VERSION 5.7 ;
  NOWIREEXTENSIONATPIN ON ;
  DIVIDERCHAR "/" ;
  BUSBITCHARS "[]" ;
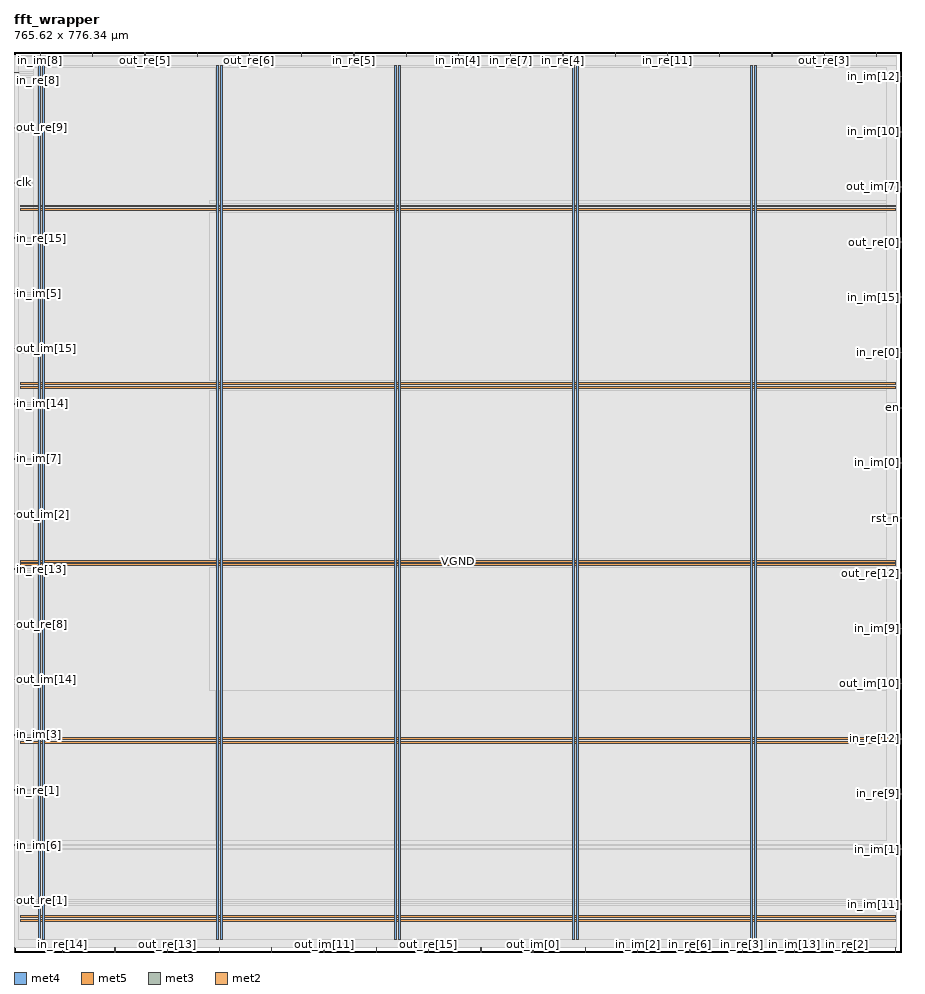
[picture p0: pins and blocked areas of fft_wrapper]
MACRO fft_wrapper
  CLASS BLOCK ;
  FOREIGN fft_wrapper ;
  ORIGIN 0.000 0.000 ;
  SIZE 765.620 BY 776.340 ;
  PIN VGND
    DIRECTION INOUT ;
    USE GROUND ;
    PORT
      LAYER met4 ;
        RECT 24.340 10.640 25.940 764.560 ;
    END
    PORT
      LAYER met4 ;
        RECT 177.940 10.640 179.540 764.560 ;
    END
    PORT
      LAYER met4 ;
        RECT 331.540 10.640 333.140 764.560 ;
    END
    PORT
      LAYER met4 ;
        RECT 485.140 10.640 486.740 764.560 ;
    END
    PORT
      LAYER met4 ;
        RECT 638.740 10.640 640.340 764.560 ;
    END
    PORT
      LAYER met5 ;
        RECT 5.280 30.030 760.160 31.630 ;
    END
    PORT
      LAYER met5 ;
        RECT 5.280 183.210 760.160 184.810 ;
    END
    PORT
      LAYER met5 ;
        RECT 5.280 336.390 760.160 337.990 ;
    END
    PORT
      LAYER met5 ;
        RECT 5.280 489.570 760.160 491.170 ;
    END
    PORT
      LAYER met5 ;
        RECT 5.280 642.750 760.160 644.350 ;
    END
  END VGND
  PIN VPWR
    DIRECTION INOUT ;
    USE POWER ;
    PORT
      LAYER met4 ;
        RECT 21.040 10.640 22.640 764.560 ;
    END
    PORT
      LAYER met4 ;
        RECT 174.640 10.640 176.240 764.560 ;
    END
    PORT
      LAYER met4 ;
        RECT 328.240 10.640 329.840 764.560 ;
    END
    PORT
      LAYER met4 ;
        RECT 481.840 10.640 483.440 764.560 ;
    END
    PORT
      LAYER met4 ;
        RECT 635.440 10.640 637.040 764.560 ;
    END
    PORT
      LAYER met5 ;
        RECT 5.280 26.730 760.160 28.330 ;
    END
    PORT
      LAYER met5 ;
        RECT 5.280 179.910 760.160 181.510 ;
    END
    PORT
      LAYER met5 ;
        RECT 5.280 333.090 760.160 334.690 ;
    END
    PORT
      LAYER met5 ;
        RECT 5.280 486.270 760.160 487.870 ;
    END
    PORT
      LAYER met5 ;
        RECT 5.280 639.450 760.160 641.050 ;
    END
  END VPWR
  PIN clk
    DIRECTION INPUT ;
    USE SIGNAL ;
    ANTENNAGATEAREA 1.286700 ;
    ANTENNADIFFAREA 0.434700 ;
    PORT
      LAYER met3 ;
        RECT 0.000 663.040 4.000 663.640 ;
    END
  END clk
  PIN en
    DIRECTION INPUT ;
    USE SIGNAL ;
    ANTENNAGATEAREA 0.247500 ;
    PORT
      LAYER met3 ;
        RECT 761.620 469.240 765.620 469.840 ;
    END
  END en
  PIN in_im[0]
    DIRECTION INPUT ;
    USE SIGNAL ;
    ANTENNAGATEAREA 0.247500 ;
    PORT
      LAYER met3 ;
        RECT 761.620 421.640 765.620 422.240 ;
    END
  END in_im[0]
  PIN in_im[10]
    DIRECTION INPUT ;
    USE SIGNAL ;
    ANTENNAGATEAREA 0.495000 ;
    PORT
      LAYER met3 ;
        RECT 761.620 707.240 765.620 707.840 ;
    END
  END in_im[10]
  PIN in_im[11]
    DIRECTION INPUT ;
    USE SIGNAL ;
    ANTENNAGATEAREA 0.426000 ;
    PORT
      LAYER met3 ;
        RECT 761.620 40.840 765.620 41.440 ;
    END
  END in_im[11]
  PIN in_im[12]
    DIRECTION INPUT ;
    USE SIGNAL ;
    ANTENNAGATEAREA 0.742500 ;
    PORT
      LAYER met3 ;
        RECT 761.620 754.840 765.620 755.440 ;
    END
  END in_im[12]
  PIN in_im[13]
    DIRECTION INPUT ;
    USE SIGNAL ;
    ANTENNAGATEAREA 0.426000 ;
    PORT
      LAYER met2 ;
        RECT 673.070 0.000 673.350 4.000 ;
    END
  END in_im[13]
  PIN in_im[14]
    DIRECTION INPUT ;
    USE SIGNAL ;
    ANTENNAGATEAREA 0.247500 ;
    PORT
      LAYER met3 ;
        RECT 0.000 472.640 4.000 473.240 ;
    END
  END in_im[14]
  PIN in_im[15]
    DIRECTION INPUT ;
    USE SIGNAL ;
    ANTENNAGATEAREA 0.426000 ;
    PORT
      LAYER met3 ;
        RECT 761.620 564.440 765.620 565.040 ;
    END
  END in_im[15]
  PIN in_im[1]
    DIRECTION INPUT ;
    USE SIGNAL ;
    ANTENNAGATEAREA 0.247500 ;
    PORT
      LAYER met3 ;
        RECT 761.620 88.440 765.620 89.040 ;
    END
  END in_im[1]
  PIN in_im[2]
    DIRECTION INPUT ;
    USE SIGNAL ;
    ANTENNAGATEAREA 0.247500 ;
    PORT
      LAYER met2 ;
        RECT 537.830 0.000 538.110 4.000 ;
    END
  END in_im[2]
  PIN in_im[3]
    DIRECTION INPUT ;
    USE SIGNAL ;
    ANTENNAGATEAREA 0.247500 ;
    PORT
      LAYER met3 ;
        RECT 0.000 187.040 4.000 187.640 ;
    END
  END in_im[3]
  PIN in_im[4]
    DIRECTION INPUT ;
    USE SIGNAL ;
    ANTENNAGATEAREA 0.247500 ;
    PORT
      LAYER met2 ;
        RECT 383.270 772.340 383.550 776.340 ;
    END
  END in_im[4]
  PIN in_im[5]
    DIRECTION INPUT ;
    USE SIGNAL ;
    ANTENNAGATEAREA 0.426000 ;
    PORT
      LAYER met3 ;
        RECT 0.000 567.840 4.000 568.440 ;
    END
  END in_im[5]
  PIN in_im[6]
    DIRECTION INPUT ;
    USE SIGNAL ;
    ANTENNAGATEAREA 0.213000 ;
    PORT
      LAYER met3 ;
        RECT 0.000 91.840 4.000 92.440 ;
    END
  END in_im[6]
  PIN in_im[7]
    DIRECTION INPUT ;
    USE SIGNAL ;
    ANTENNAGATEAREA 0.247500 ;
    PORT
      LAYER met3 ;
        RECT 0.000 425.040 4.000 425.640 ;
    END
  END in_im[7]
  PIN in_im[8]
    DIRECTION INPUT ;
    USE SIGNAL ;
    ANTENNAGATEAREA 0.742500 ;
    PORT
      LAYER met2 ;
        RECT 22.630 772.340 22.910 776.340 ;
    END
  END in_im[8]
  PIN in_im[9]
    DIRECTION INPUT ;
    USE SIGNAL ;
    ANTENNAGATEAREA 0.247500 ;
    PORT
      LAYER met3 ;
        RECT 761.620 278.840 765.620 279.440 ;
    END
  END in_im[9]
  PIN in_re[0]
    DIRECTION INPUT ;
    USE SIGNAL ;
    ANTENNAGATEAREA 0.426000 ;
    PORT
      LAYER met3 ;
        RECT 761.620 516.840 765.620 517.440 ;
    END
  END in_re[0]
  PIN in_re[10]
    DIRECTION INPUT ;
    USE SIGNAL ;
    ANTENNAGATEAREA 0.247500 ;
    PORT
      LAYER met2 ;
        RECT 177.190 0.000 177.470 4.000 ;
    END
  END in_re[10]
  PIN in_re[11]
    DIRECTION INPUT ;
    USE SIGNAL ;
    ANTENNAGATEAREA 0.426000 ;
    PORT
      LAYER met2 ;
        RECT 563.590 772.340 563.870 776.340 ;
    END
  END in_re[11]
  PIN in_re[12]
    DIRECTION INPUT ;
    USE SIGNAL ;
    ANTENNAGATEAREA 0.247500 ;
    PORT
      LAYER met3 ;
        RECT 761.620 183.640 765.620 184.240 ;
    END
  END in_re[12]
  PIN in_re[13]
    DIRECTION INPUT ;
    USE SIGNAL ;
    ANTENNAGATEAREA 0.213000 ;
    PORT
      LAYER met3 ;
        RECT 0.000 329.840 4.000 330.440 ;
    END
  END in_re[13]
  PIN in_re[14]
    DIRECTION INPUT ;
    USE SIGNAL ;
    ANTENNAGATEAREA 0.426000 ;
    PORT
      LAYER met2 ;
        RECT 41.950 0.000 42.230 4.000 ;
    END
  END in_re[14]
  PIN in_re[15]
    DIRECTION INPUT ;
    USE SIGNAL ;
    ANTENNAGATEAREA 0.247500 ;
    PORT
      LAYER met3 ;
        RECT 0.000 615.440 4.000 616.040 ;
    END
  END in_re[15]
  PIN in_re[1]
    DIRECTION INPUT ;
    USE SIGNAL ;
    ANTENNAGATEAREA 0.247500 ;
    PORT
      LAYER met3 ;
        RECT 0.000 139.440 4.000 140.040 ;
    END
  END in_re[1]
  PIN in_re[2]
    DIRECTION INPUT ;
    USE SIGNAL ;
    ANTENNAGATEAREA 0.247500 ;
    PORT
      LAYER met2 ;
        RECT 718.150 0.000 718.430 4.000 ;
    END
  END in_re[2]
  PIN in_re[3]
    DIRECTION INPUT ;
    USE SIGNAL ;
    ANTENNAGATEAREA 0.426000 ;
    PORT
      LAYER met2 ;
        RECT 627.990 0.000 628.270 4.000 ;
    END
  END in_re[3]
  PIN in_re[4]
    DIRECTION INPUT ;
    USE SIGNAL ;
    ANTENNAGATEAREA 0.495000 ;
    PORT
      LAYER met2 ;
        RECT 473.430 772.340 473.710 776.340 ;
    END
  END in_re[4]
  PIN in_re[5]
    DIRECTION INPUT ;
    USE SIGNAL ;
    ANTENNAGATEAREA 0.426000 ;
    PORT
      LAYER met2 ;
        RECT 293.110 772.340 293.390 776.340 ;
    END
  END in_re[5]
  PIN in_re[6]
    DIRECTION INPUT ;
    USE SIGNAL ;
    ANTENNAGATEAREA 0.213000 ;
    PORT
      LAYER met2 ;
        RECT 582.910 0.000 583.190 4.000 ;
    END
  END in_re[6]
  PIN in_re[7]
    DIRECTION INPUT ;
    USE SIGNAL ;
    ANTENNAGATEAREA 0.426000 ;
    PORT
      LAYER met2 ;
        RECT 428.350 772.340 428.630 776.340 ;
    END
  END in_re[7]
  PIN in_re[8]
    DIRECTION INPUT ;
    USE SIGNAL ;
    ANTENNAGATEAREA 0.495000 ;
    PORT
      LAYER met3 ;
        RECT 0.000 758.240 4.000 758.840 ;
    END
  END in_re[8]
  PIN in_re[9]
    DIRECTION INPUT ;
    USE SIGNAL ;
    ANTENNAGATEAREA 0.247500 ;
    PORT
      LAYER met3 ;
        RECT 761.620 136.040 765.620 136.640 ;
    END
  END in_re[9]
  PIN out_im[0]
    DIRECTION OUTPUT TRISTATE ;
    USE SIGNAL ;
    ANTENNADIFFAREA 0.340600 ;
    PORT
      LAYER met2 ;
        RECT 447.670 0.000 447.950 4.000 ;
    END
  END out_im[0]
  PIN out_im[10]
    DIRECTION OUTPUT TRISTATE ;
    USE SIGNAL ;
    ANTENNADIFFAREA 0.340600 ;
    PORT
      LAYER met3 ;
        RECT 761.620 231.240 765.620 231.840 ;
    END
  END out_im[10]
  PIN out_im[11]
    DIRECTION OUTPUT TRISTATE ;
    USE SIGNAL ;
    ANTENNADIFFAREA 0.340600 ;
    PORT
      LAYER met2 ;
        RECT 267.350 0.000 267.630 4.000 ;
    END
  END out_im[11]
  PIN out_im[12]
    DIRECTION OUTPUT TRISTATE ;
    USE SIGNAL ;
    ANTENNADIFFAREA 0.340600 ;
    PORT
      LAYER met2 ;
        RECT 608.670 772.340 608.950 776.340 ;
    END
  END out_im[12]
  PIN out_im[13]
    DIRECTION OUTPUT TRISTATE ;
    USE SIGNAL ;
    ANTENNADIFFAREA 0.340600 ;
    PORT
      LAYER met2 ;
        RECT 67.710 772.340 67.990 776.340 ;
    END
  END out_im[13]
  PIN out_im[14]
    DIRECTION OUTPUT TRISTATE ;
    USE SIGNAL ;
    ANTENNADIFFAREA 0.340600 ;
    PORT
      LAYER met3 ;
        RECT 0.000 234.640 4.000 235.240 ;
    END
  END out_im[14]
  PIN out_im[15]
    DIRECTION OUTPUT TRISTATE ;
    USE SIGNAL ;
    ANTENNADIFFAREA 0.340600 ;
    PORT
      LAYER met3 ;
        RECT 0.000 520.240 4.000 520.840 ;
    END
  END out_im[15]
  PIN out_im[1]
    DIRECTION OUTPUT TRISTATE ;
    USE SIGNAL ;
    ANTENNADIFFAREA 0.340600 ;
    PORT
      LAYER met2 ;
        RECT 518.510 772.340 518.790 776.340 ;
    END
  END out_im[1]
  PIN out_im[2]
    DIRECTION OUTPUT TRISTATE ;
    USE SIGNAL ;
    ANTENNADIFFAREA 0.340600 ;
    PORT
      LAYER met3 ;
        RECT 0.000 377.440 4.000 378.040 ;
    END
  END out_im[2]
  PIN out_im[3]
    DIRECTION OUTPUT TRISTATE ;
    USE SIGNAL ;
    ANTENNADIFFAREA 0.340600 ;
    PORT
      LAYER met2 ;
        RECT 157.870 772.340 158.150 776.340 ;
    END
  END out_im[3]
  PIN out_im[4]
    DIRECTION OUTPUT TRISTATE ;
    USE SIGNAL ;
    ANTENNADIFFAREA 0.340600 ;
    PORT
      LAYER met2 ;
        RECT 338.190 772.340 338.470 776.340 ;
    END
  END out_im[4]
  PIN out_im[5]
    DIRECTION OUTPUT TRISTATE ;
    USE SIGNAL ;
    ANTENNADIFFAREA 0.340600 ;
    PORT
      LAYER met2 ;
        RECT 87.030 0.000 87.310 4.000 ;
    END
  END out_im[5]
  PIN out_im[6]
    DIRECTION OUTPUT TRISTATE ;
    USE SIGNAL ;
    ANTENNADIFFAREA 0.340600 ;
    PORT
      LAYER met2 ;
        RECT 0.090 0.000 0.370 4.000 ;
    END
  END out_im[6]
  PIN out_im[7]
    DIRECTION OUTPUT TRISTATE ;
    USE SIGNAL ;
    ANTENNADIFFAREA 0.340600 ;
    PORT
      LAYER met3 ;
        RECT 761.620 659.640 765.620 660.240 ;
    END
  END out_im[7]
  PIN out_im[8]
    DIRECTION OUTPUT TRISTATE ;
    USE SIGNAL ;
    ANTENNADIFFAREA 0.340600 ;
    PORT
      LAYER met2 ;
        RECT 743.910 772.340 744.190 776.340 ;
    END
  END out_im[8]
  PIN out_im[9]
    DIRECTION OUTPUT TRISTATE ;
    USE SIGNAL ;
    ANTENNADIFFAREA 0.340600 ;
    PORT
      LAYER met2 ;
        RECT 312.430 0.000 312.710 4.000 ;
    END
  END out_im[9]
  PIN out_re[0]
    DIRECTION OUTPUT TRISTATE ;
    USE SIGNAL ;
    ANTENNADIFFAREA 0.340600 ;
    PORT
      LAYER met3 ;
        RECT 761.620 612.040 765.620 612.640 ;
    END
  END out_re[0]
  PIN out_re[10]
    DIRECTION OUTPUT TRISTATE ;
    USE SIGNAL ;
    ANTENNADIFFAREA 0.340600 ;
    PORT
      LAYER met2 ;
        RECT 760.010 0.000 760.290 4.000 ;
    END
  END out_re[10]
  PIN out_re[11]
    DIRECTION OUTPUT TRISTATE ;
    USE SIGNAL ;
    ANTENNADIFFAREA 0.340600 ;
    PORT
      LAYER met2 ;
        RECT 248.030 772.340 248.310 776.340 ;
    END
  END out_re[11]
  PIN out_re[12]
    DIRECTION OUTPUT TRISTATE ;
    USE SIGNAL ;
    ANTENNADIFFAREA 0.340600 ;
    PORT
      LAYER met3 ;
        RECT 761.620 326.440 765.620 327.040 ;
    END
  END out_re[12]
  PIN out_re[13]
    DIRECTION OUTPUT TRISTATE ;
    USE SIGNAL ;
    ANTENNADIFFAREA 0.340600 ;
    PORT
      LAYER met2 ;
        RECT 132.110 0.000 132.390 4.000 ;
    END
  END out_re[13]
  PIN out_re[14]
    DIRECTION OUTPUT TRISTATE ;
    USE SIGNAL ;
    ANTENNADIFFAREA 0.340600 ;
    PORT
      LAYER met2 ;
        RECT 222.270 0.000 222.550 4.000 ;
    END
  END out_re[14]
  PIN out_re[15]
    DIRECTION OUTPUT TRISTATE ;
    USE SIGNAL ;
    ANTENNADIFFAREA 0.340600 ;
    PORT
      LAYER met2 ;
        RECT 357.510 0.000 357.790 4.000 ;
    END
  END out_re[15]
  PIN out_re[1]
    DIRECTION OUTPUT TRISTATE ;
    USE SIGNAL ;
    ANTENNADIFFAREA 0.340600 ;
    PORT
      LAYER met3 ;
        RECT 0.000 44.240 4.000 44.840 ;
    END
  END out_re[1]
  PIN out_re[2]
    DIRECTION OUTPUT TRISTATE ;
    USE SIGNAL ;
    ANTENNADIFFAREA 0.340600 ;
    PORT
      LAYER met2 ;
        RECT 402.590 0.000 402.870 4.000 ;
    END
  END out_re[2]
  PIN out_re[3]
    DIRECTION OUTPUT TRISTATE ;
    USE SIGNAL ;
    ANTENNADIFFAREA 0.340600 ;
    PORT
      LAYER met2 ;
        RECT 698.830 772.340 699.110 776.340 ;
    END
  END out_re[3]
  PIN out_re[4]
    DIRECTION OUTPUT TRISTATE ;
    USE SIGNAL ;
    ANTENNADIFFAREA 0.340600 ;
    PORT
      LAYER met2 ;
        RECT 653.750 772.340 654.030 776.340 ;
    END
  END out_re[4]
  PIN out_re[5]
    DIRECTION OUTPUT TRISTATE ;
    USE SIGNAL ;
    ANTENNADIFFAREA 0.340600 ;
    PORT
      LAYER met2 ;
        RECT 112.790 772.340 113.070 776.340 ;
    END
  END out_re[5]
  PIN out_re[6]
    DIRECTION OUTPUT TRISTATE ;
    USE SIGNAL ;
    ANTENNADIFFAREA 0.340600 ;
    PORT
      LAYER met2 ;
        RECT 202.950 772.340 203.230 776.340 ;
    END
  END out_re[6]
  PIN out_re[7]
    DIRECTION OUTPUT TRISTATE ;
    USE SIGNAL ;
    ANTENNADIFFAREA 0.340600 ;
    PORT
      LAYER met2 ;
        RECT 492.750 0.000 493.030 4.000 ;
    END
  END out_re[7]
  PIN out_re[8]
    DIRECTION OUTPUT TRISTATE ;
    USE SIGNAL ;
    ANTENNADIFFAREA 0.340600 ;
    PORT
      LAYER met3 ;
        RECT 0.000 282.240 4.000 282.840 ;
    END
  END out_re[8]
  PIN out_re[9]
    DIRECTION OUTPUT TRISTATE ;
    USE SIGNAL ;
    ANTENNADIFFAREA 0.340600 ;
    PORT
      LAYER met3 ;
        RECT 0.000 710.640 4.000 711.240 ;
    END
  END out_re[9]
  PIN rst_n
    DIRECTION INPUT ;
    USE SIGNAL ;
    ANTENNAGATEAREA 0.990000 ;
    PORT
      LAYER met3 ;
        RECT 761.620 374.040 765.620 374.640 ;
    END
  END rst_n
  OBS
      LAYER li1 ;
        RECT 5.520 10.795 759.920 764.405 ;
      LAYER met1 ;
        RECT 0.070 10.640 761.230 764.560 ;
      LAYER met2 ;
        RECT 0.100 772.060 22.350 772.890 ;
        RECT 23.190 772.060 67.430 772.890 ;
        RECT 68.270 772.060 112.510 772.890 ;
        RECT 113.350 772.060 157.590 772.890 ;
        RECT 158.430 772.060 202.670 772.890 ;
        RECT 203.510 772.060 247.750 772.890 ;
        RECT 248.590 772.060 292.830 772.890 ;
        RECT 293.670 772.060 337.910 772.890 ;
        RECT 338.750 772.060 382.990 772.890 ;
        RECT 383.830 772.060 428.070 772.890 ;
        RECT 428.910 772.060 473.150 772.890 ;
        RECT 473.990 772.060 518.230 772.890 ;
        RECT 519.070 772.060 563.310 772.890 ;
        RECT 564.150 772.060 608.390 772.890 ;
        RECT 609.230 772.060 653.470 772.890 ;
        RECT 654.310 772.060 698.550 772.890 ;
        RECT 699.390 772.060 743.630 772.890 ;
        RECT 744.470 772.060 761.210 772.890 ;
        RECT 0.100 4.280 761.210 772.060 ;
        RECT 0.650 4.000 41.670 4.280 ;
        RECT 42.510 4.000 86.750 4.280 ;
        RECT 87.590 4.000 131.830 4.280 ;
        RECT 132.670 4.000 176.910 4.280 ;
        RECT 177.750 4.000 221.990 4.280 ;
        RECT 222.830 4.000 267.070 4.280 ;
        RECT 267.910 4.000 312.150 4.280 ;
        RECT 312.990 4.000 357.230 4.280 ;
        RECT 358.070 4.000 402.310 4.280 ;
        RECT 403.150 4.000 447.390 4.280 ;
        RECT 448.230 4.000 492.470 4.280 ;
        RECT 493.310 4.000 537.550 4.280 ;
        RECT 538.390 4.000 582.630 4.280 ;
        RECT 583.470 4.000 627.710 4.280 ;
        RECT 628.550 4.000 672.790 4.280 ;
        RECT 673.630 4.000 717.870 4.280 ;
        RECT 718.710 4.000 759.730 4.280 ;
        RECT 760.570 4.000 761.210 4.280 ;
      LAYER met3 ;
        RECT 3.990 759.240 761.620 764.485 ;
        RECT 4.400 757.840 761.620 759.240 ;
        RECT 3.990 755.840 761.620 757.840 ;
        RECT 3.990 754.440 761.220 755.840 ;
        RECT 3.990 711.640 761.620 754.440 ;
        RECT 4.400 710.240 761.620 711.640 ;
        RECT 3.990 708.240 761.620 710.240 ;
        RECT 3.990 706.840 761.220 708.240 ;
        RECT 3.990 664.040 761.620 706.840 ;
        RECT 4.400 662.640 761.620 664.040 ;
        RECT 3.990 660.640 761.620 662.640 ;
        RECT 3.990 659.240 761.220 660.640 ;
        RECT 3.990 616.440 761.620 659.240 ;
        RECT 4.400 615.040 761.620 616.440 ;
        RECT 3.990 613.040 761.620 615.040 ;
        RECT 3.990 611.640 761.220 613.040 ;
        RECT 3.990 568.840 761.620 611.640 ;
        RECT 4.400 567.440 761.620 568.840 ;
        RECT 3.990 565.440 761.620 567.440 ;
        RECT 3.990 564.040 761.220 565.440 ;
        RECT 3.990 521.240 761.620 564.040 ;
        RECT 4.400 519.840 761.620 521.240 ;
        RECT 3.990 517.840 761.620 519.840 ;
        RECT 3.990 516.440 761.220 517.840 ;
        RECT 3.990 473.640 761.620 516.440 ;
        RECT 4.400 472.240 761.620 473.640 ;
        RECT 3.990 470.240 761.620 472.240 ;
        RECT 3.990 468.840 761.220 470.240 ;
        RECT 3.990 426.040 761.620 468.840 ;
        RECT 4.400 424.640 761.620 426.040 ;
        RECT 3.990 422.640 761.620 424.640 ;
        RECT 3.990 421.240 761.220 422.640 ;
        RECT 3.990 378.440 761.620 421.240 ;
        RECT 4.400 377.040 761.620 378.440 ;
        RECT 3.990 375.040 761.620 377.040 ;
        RECT 3.990 373.640 761.220 375.040 ;
        RECT 3.990 330.840 761.620 373.640 ;
        RECT 4.400 329.440 761.620 330.840 ;
        RECT 3.990 327.440 761.620 329.440 ;
        RECT 3.990 326.040 761.220 327.440 ;
        RECT 3.990 283.240 761.620 326.040 ;
        RECT 4.400 281.840 761.620 283.240 ;
        RECT 3.990 279.840 761.620 281.840 ;
        RECT 3.990 278.440 761.220 279.840 ;
        RECT 3.990 235.640 761.620 278.440 ;
        RECT 4.400 234.240 761.620 235.640 ;
        RECT 3.990 232.240 761.620 234.240 ;
        RECT 3.990 230.840 761.220 232.240 ;
        RECT 3.990 188.040 761.620 230.840 ;
        RECT 4.400 186.640 761.620 188.040 ;
        RECT 3.990 184.640 761.620 186.640 ;
        RECT 3.990 183.240 761.220 184.640 ;
        RECT 3.990 140.440 761.620 183.240 ;
        RECT 4.400 139.040 761.620 140.440 ;
        RECT 3.990 137.040 761.620 139.040 ;
        RECT 3.990 135.640 761.220 137.040 ;
        RECT 3.990 92.840 761.620 135.640 ;
        RECT 4.400 91.440 761.620 92.840 ;
        RECT 3.990 89.440 761.620 91.440 ;
        RECT 3.990 88.040 761.220 89.440 ;
        RECT 3.990 45.240 761.620 88.040 ;
        RECT 4.400 43.840 761.620 45.240 ;
        RECT 3.990 41.840 761.620 43.840 ;
        RECT 3.990 40.440 761.220 41.840 ;
        RECT 3.990 10.715 761.620 40.440 ;
      LAYER met4 ;
        RECT 16.855 96.055 20.640 762.785 ;
        RECT 23.040 96.055 23.940 762.785 ;
        RECT 26.340 96.055 174.240 762.785 ;
        RECT 176.640 96.055 177.540 762.785 ;
        RECT 179.940 96.055 327.840 762.785 ;
        RECT 330.240 96.055 331.140 762.785 ;
        RECT 333.540 96.055 481.440 762.785 ;
        RECT 483.840 96.055 484.740 762.785 ;
        RECT 487.140 96.055 635.040 762.785 ;
        RECT 637.440 96.055 638.340 762.785 ;
        RECT 640.740 96.055 752.690 762.785 ;
      LAYER met5 ;
        RECT 168.940 645.950 752.900 648.500 ;
        RECT 168.940 492.770 752.900 637.850 ;
        RECT 168.940 339.590 752.900 484.670 ;
        RECT 168.940 225.300 752.900 331.490 ;
  END
END fft_wrapper
END LIBRARY

